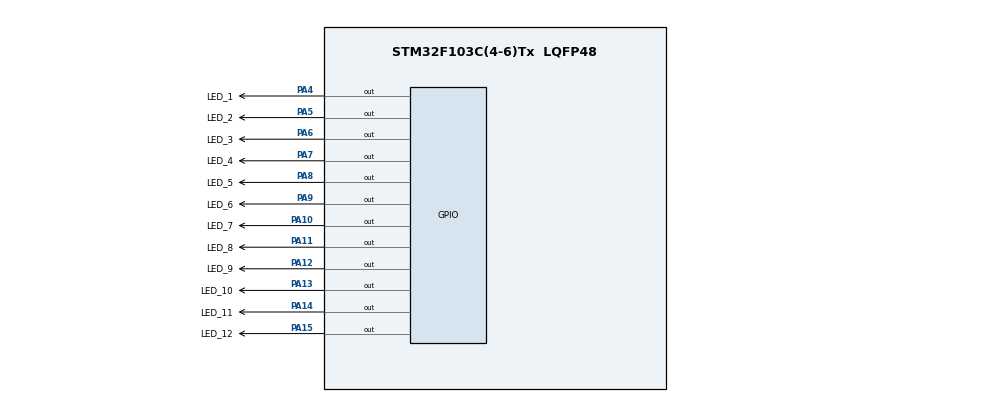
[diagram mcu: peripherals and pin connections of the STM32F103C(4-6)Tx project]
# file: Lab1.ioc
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Mcu.Family=STM32F1
Mcu.Name=STM32F103C(4-6)Tx
Mcu.Package=LQFP48
NVIC.PriorityGroup=NVIC_PRIORITYGROUP_4
PA10.GPIO_Label=LED_7
PA10.Signal=GPIO_Output
PA11.GPIO_Label=LED_8
PA11.Signal=GPIO_Output
PA12.GPIO_Label=LED_9
PA12.Signal=GPIO_Output
PA13.GPIO_Label=LED_10
PA13.Signal=GPIO_Output
PA14.GPIO_Label=LED_11
PA14.Signal=GPIO_Output
PA15.GPIO_Label=LED_12
PA15.Signal=GPIO_Output
PA4.GPIO_Label=LED_1
PA4.Signal=GPIO_Output
PA5.GPIO_Label=LED_2
PA5.Signal=GPIO_Output
PA6.GPIO_Label=LED_3
PA6.Signal=GPIO_Output
PA7.GPIO_Label=LED_4
PA7.Signal=GPIO_Output
PA8.GPIO_Label=LED_5
PA8.Signal=GPIO_Output
PA9.GPIO_Label=LED_6
PA9.Signal=GPIO_Output
ProjectManager.HeapSize=0x200
ProjectManager.StackSize=0x400
ProjectManager.TargetToolchain=STM32CubeIDE
RCC.APB1Freq_Value=8000000
RCC.APB2Freq_Value=8000000
VP_SYS_VS_ND.Mode=No_Debug
board=custom

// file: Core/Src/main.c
/* USER CODE BEGIN Header */
/**
  ******************************************************************************
  * @file           : main.c
  * @brief          : Main program body
  ******************************************************************************
  * @attention
  *
  * <h2><center>&copy; Copyright (c) 2024 STMicroelectronics.
  * All rights reserved.</center></h2>
  *
  * This software component is licensed by ST under BSD 3-Clause license,
  * the "License"; You may not use this file except in compliance with the
  * License. You may obtain a copy of the License at:
  *                        opensource.org/licenses/BSD-3-Clause
  *
  ******************************************************************************
  */
/* USER CODE END Header */
#include "main.h"

void SystemClock_Config(void);
static void MX_GPIO_Init(void);

int main(void)
{

  /* MCU Configuration--------------------------------------------------------*/

  /* Reset of all peripherals, Initializes the Flash interface and the Systick. */
  HAL_Init();

  /* Configure the system clock */
  SystemClock_Config();

  /* Initialize all configured peripherals */
  MX_GPIO_Init();

  /* Infinite loop */
  /* USER CODE BEGIN WHILE */
  void display7SEG(int num, uint32_t GPIO_Pin)
  {
      char segNumber[10] = {0xC0, 0xF9, 0xA4, 0xB0, 0x99, 0x92, 0x82, 0xF8, 0x80, 0x90};

      HAL_GPIO_WritePin(GPIOB, GPIO_Pin << 0, (segNumber[num] >> 0) & 1);
      HAL_GPIO_WritePin(GPIOB, GPIO_Pin << 1, (segNumber[num] >> 1) & 1);
      HAL_GPIO_WritePin(GPIOB, GPIO_Pin << 2, (segNumber[num] >> 2) & 1);
      HAL_GPIO_WritePin(GPIOB, GPIO_Pin << 3, (segNumber[num] >> 3) & 1);
      HAL_GPIO_WritePin(GPIOB, GPIO_Pin << 4, (segNumber[num] >> 4) & 1);
      HAL_GPIO_WritePin(GPIOB, GPIO_Pin << 5, (segNumber[num] >> 5) & 1);
      HAL_GPIO_WritePin(GPIOB, GPIO_Pin << 6, (segNumber[num] >> 6) & 1);
  }

  int countRed = 5, countYellow = 2, countGreen = 3, cross = 1;
  while (1)
  {
	  switch (cross)
	  {
	  	  case 1:
	  	  {
	  		  if (countRed > 0)
	  		  {
	  			  display7SEG(countRed, GPIO_PIN_7);
	  			  switch (countRed)
	  			  {
	  			  	  case 1 ... 2:
	  			  	  {
	  			  		  HAL_GPIO_WritePin(GPIOA, LED_RED_Pin, RESET);
	  			  		  HAL_GPIO_WritePin(GPIOA, LED_YELLOW_Pin, SET);
	  			  		  HAL_GPIO_WritePin(GPIOA, LED_GREEN_Pin, SET);

	  			  		  HAL_GPIO_WritePin(GPIOA, LED_RED1_Pin, SET);
	  			  		  HAL_GPIO_WritePin(GPIOA, LED_YELLOW1_Pin, RESET);
	  			  		  HAL_GPIO_WritePin(GPIOA, LED_GREEN1_Pin, SET);

	  			  		  display7SEG(countYellow, GPIO_PIN_0);
	  			  		  countYellow--;
	  			  		  break;
	  			  	  }
	  			  	  case 3 ... 5:
	  			  	  {
	  			  		  HAL_GPIO_WritePin(GPIOA, LED_RED_Pin, RESET);
	  			  		  HAL_GPIO_WritePin(GPIOA, LED_YELLOW_Pin, SET);
	  			  		  HAL_GPIO_WritePin(GPIOA, LED_GREEN_Pin, SET);

	  			  		  HAL_GPIO_WritePin(GPIOA, LED_RED1_Pin, SET);
	  			  		  HAL_GPIO_WritePin(GPIOA, LED_YELLOW1_Pin, SET);
	  			  		  HAL_GPIO_WritePin(GPIOA, LED_GREEN1_Pin, RESET);

	  			  		  display7SEG(countGreen, GPIO_PIN_0);
	  			  		  countGreen--;
	  			  		  break;
	  			  	  }
	  			  }
	  			  countRed--;
	  		  }
	  		  if (countYellow == 0) countYellow = 2;
	  		  if (countGreen == 0) countGreen = 3;
	  		  if (countRed == 0)
	  		  {
	  			  countRed += 5;
	  			  cross = 2;
	  		  }
	  		  break;
	  	  }
	  	  case 2:
	  	  {
	  		  if (countRed > 0)
	  		  {
	  			  display7SEG(countRed, GPIO_PIN_0);
	  			  switch (countRed)
	  			  {

	  			  	  case 1 ... 2:
	  			  	  {
	  			  		  HAL_GPIO_WritePin(GPIOA, LED_RED1_Pin, RESET);
	  			  		  HAL_GPIO_WritePin(GPIOA, LED_YELLOW1_Pin, SET);
	  			  		  HAL_GPIO_WritePin(GPIOA, LED_GREEN1_Pin, SET);

	  			  		  HAL_GPIO_WritePin(GPIOA, LED_RED_Pin, SET);
	  			  		  HAL_GPIO_WritePin(GPIOA, LED_YELLOW_Pin, RESET);
	  			  		  HAL_GPIO_WritePin(GPIOA, LED_GREEN_Pin, SET);

	  			  		  display7SEG(countYellow, GPIO_PIN_7);
	  			  		  countYellow--;
	  			  		  break;
	  			  	  }
	  			  	  case 3 ... 5:
	  			  	  {
	  			  		  HAL_GPIO_WritePin(GPIOA, LED_RED1_Pin, RESET);
	  			  		  HAL_GPIO_WritePin(GPIOA, LED_YELLOW1_Pin, SET);
	  			  		  HAL_GPIO_WritePin(GPIOA, LED_GREEN1_Pin, SET);

	  			  		  HAL_GPIO_WritePin(GPIOA, LED_RED_Pin, SET);
	  			  		  HAL_GPIO_WritePin(GPIOA, LED_YELLOW_Pin, SET);
	  			  		  HAL_GPIO_WritePin(GPIOA, LED_GREEN_Pin, RESET);
	  			  		  display7SEG(countGreen, GPIO_PIN_7);
	  			  		  countGreen--;
	  			  		  break;
	  			  	  }

	  			  }
	  			  countRed--;
	  		  }
	  		  if (countYellow == 0) countYellow = 2;
	  		  if (countGreen == 0) countGreen = 3;
	  		  if (countRed == 0)
	  		  {
	  			  countRed += 5;
	  			  cross = 1;
	  		  }
	  		  break;
	  	  }
	  }
	  HAL_Delay(1000);
    /* USER CODE END WHILE */

  }
}

void SystemClock_Config(void)
{
  RCC_OscInitTypeDef RCC_OscInitStruct = {0};
  RCC_ClkInitTypeDef RCC_ClkInitStruct = {0};

  /** Initializes the RCC Oscillators according to the specified parameters
  * in the RCC_OscInitTypeDef structure.
  */
  RCC_OscInitStruct.OscillatorType = RCC_OSCILLATORTYPE_HSI;
  RCC_OscInitStruct.HSIState = RCC_HSI_ON;
  RCC_OscInitStruct.HSICalibrationValue = RCC_HSICALIBRATION_DEFAULT;
  RCC_OscInitStruct.PLL.PLLState = RCC_PLL_NONE;
  if (HAL_RCC_OscConfig(&RCC_OscInitStruct) != HAL_OK)
  {
    Error_Handler();
  }
  /** Initializes the CPU, AHB and APB buses clocks
  */
  RCC_ClkInitStruct.ClockType = RCC_CLOCKTYPE_HCLK|RCC_CLOCKTYPE_SYSCLK
                              |RCC_CLOCKTYPE_PCLK1|RCC_CLOCKTYPE_PCLK2;
  RCC_ClkInitStruct.SYSCLKSource = RCC_SYSCLKSOURCE_HSI;
  RCC_ClkInitStruct.AHBCLKDivider = RCC_SYSCLK_DIV1;
  RCC_ClkInitStruct.APB1CLKDivider = RCC_HCLK_DIV1;
  RCC_ClkInitStruct.APB2CLKDivider = RCC_HCLK_DIV1;

  if (HAL_RCC_ClockConfig(&RCC_ClkInitStruct, FLASH_LATENCY_0) != HAL_OK)
  {
    Error_Handler();
  }
}

static void MX_GPIO_Init(void)
{
  GPIO_InitTypeDef GPIO_InitStruct = {0};

  /* GPIO Ports Clock Enable */
  __HAL_RCC_GPIOA_CLK_ENABLE();
  __HAL_RCC_GPIOB_CLK_ENABLE();

  /*Configure GPIO pin Output Level */
  HAL_GPIO_WritePin(GPIOA, LED_RED1_Pin|LED_YELLOW1_Pin|LED_GREEN1_Pin|LED_RED_Pin
                          |LED_YELLOW_Pin|LED_GREEN_Pin, GPIO_PIN_RESET);

  /*Configure GPIO pin Output Level */
  HAL_GPIO_WritePin(GPIOB, GPIOA_Pin|GPIOB_Pin|GPIOC_Pin|GPIOD1_Pin
                          |GPIOE1_Pin|GPIOF1_Pin|GPIOG1_Pin|GPIOD_Pin
                          |GPIOE_Pin|GPIOF_Pin|GPIOG_Pin|GPIOA1_Pin
                          |GPIOB1_Pin|GPIOC1_Pin, GPIO_PIN_RESET);

  /*Configure GPIO pins : LED_RED1_Pin LED_YELLOW1_Pin LED_GREEN1_Pin LED_RED_Pin
                           LED_YELLOW_Pin LED_GREEN_Pin */
  GPIO_InitStruct.Pin = LED_RED1_Pin|LED_YELLOW1_Pin|LED_GREEN1_Pin|LED_RED_Pin
                          |LED_YELLOW_Pin|LED_GREEN_Pin;
  GPIO_InitStruct.Mode = GPIO_MODE_OUTPUT_PP;
  GPIO_InitStruct.Pull = GPIO_NOPULL;
  GPIO_InitStruct.Speed = GPIO_SPEED_FREQ_LOW;
  HAL_GPIO_Init(GPIOA, &GPIO_InitStruct);

  /*Configure GPIO pins : GPIOA_Pin GPIOB_Pin GPIOC_Pin GPIOD1_Pin
                           GPIOE1_Pin GPIOF1_Pin GPIOG1_Pin GPIOD_Pin
                           GPIOE_Pin GPIOF_Pin GPIOG_Pin GPIOA1_Pin
                           GPIOB1_Pin GPIOC1_Pin */
  GPIO_InitStruct.Pin = GPIOA_Pin|GPIOB_Pin|GPIOC_Pin|GPIOD1_Pin
                          |GPIOE1_Pin|GPIOF1_Pin|GPIOG1_Pin|GPIOD_Pin
                          |GPIOE_Pin|GPIOF_Pin|GPIOG_Pin|GPIOA1_Pin
                          |GPIOB1_Pin|GPIOC1_Pin;
  GPIO_InitStruct.Mode = GPIO_MODE_OUTPUT_PP;
  GPIO_InitStruct.Pull = GPIO_NOPULL;
  GPIO_InitStruct.Speed = GPIO_SPEED_FREQ_LOW;
  HAL_GPIO_Init(GPIOB, &GPIO_InitStruct);

}

void Error_Handler(void)
{
  __disable_irq();
  while (1)
  {
  }
}

/************************ (C) COPYRIGHT STMicroelectronics *****END OF FILE****/
